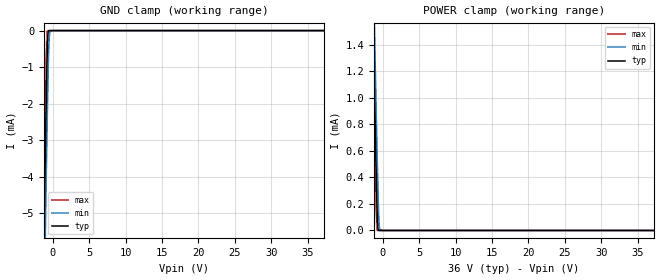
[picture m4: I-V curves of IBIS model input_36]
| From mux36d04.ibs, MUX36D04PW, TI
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|   input_36 Model
[Model]   input_36
Model_type   Input
Vinl = 0.8
Vinh = 2
|   typ   min   max
|   (nom PVT)   (fast PVT)   (slow PVT)
C_comp   4.668e-13   4.630e-13   4.694e-13
| Where nom  PVT is Nominal Process, 36V, 27C
|   Fast PVT is Strong Process,  36.1V, -40C
|   Slow PVT is Weak Process,   35.9V, 125C
[Voltage Range]   36   35.9   36.1
|Junction Temperature
[Temperature Range]   27   125   -40
[Power Clamp Reference]   36   35.9   36.1
[GND Clamp Reference]   0   0   0
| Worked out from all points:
|   GND clamp passes 1 mA (typ) near -0.80 V on its own axis
|   POWER clamp passes 1 mA (typ) near -1.11 V on its own axis
[GND Clamp]
|   Voltage   I(typ)   I(min)   I(max)
-36V      -526.6mA   -551mA     -503mA
-1.392V   -8.158mA   -10.27mA   -6.768mA
-1.236V   -6.138mA   -8.264mA   -4.733mA
-1.213V   -5.847mA   -7.973mA   -4.441mA
-1.019V   -3.42mA    -5.538mA   -2.029mA
-838.6mV  -1.34mA    -3.355mA   -246.1uA
-756mV    -573uA     -2.412mA   -20.47uA
-684mV    -160uA     -1.645mA   -1.055uA
-566.7mV  -6.25uA    -617uA     0A
-494.9mV  -529.9nA   -229.8uA   0A
-135.9mV  0A         -33.54nA   0A
72V       0A         0A         0A
[POWER Clamp]
|   Voltage   I(typ)   I(min)   I(max)
-36V      279.5mA    363.1mA    196.1mA
-1.416V   1.852mA    2.31mA     1.562mA
-1.357V   1.683mA    2.144mA    1.39mA
-1.236V   1.343mA    1.809mA    1.045mA
-1.152V   1.11mA     1.578mA    809.5uA
-900mV    438uA      900.6uA    156.6uA
-838.6mV  289.6uA    741.4uA    47.21uA
-730.3mV  77.86uA    471.9uA    700.2nA
-612mV    2.993uA    210.8uA    0A
-494.9mV  46.11nA    42.15uA    0A
-28.2mV   0A         0A         0A
72V       0A         0A         0A
